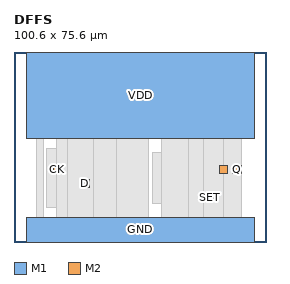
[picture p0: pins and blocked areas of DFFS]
MACRO DFFS
  CLASS CORE ;
  ORIGIN 0 0 ;
  SIZE 100.600 BY 75.600 ;
  SYMMETRY X Y ;
  SITE TR1um_access_site ;
  PIN VDD
    DIRECTION INOUT ;
    USE POWER ;
    PORT
      LAYER M1 ;
        RECT 5.000 41.000 95.600 75.600 ;
    END
  END VDD
  PIN GND
    DIRECTION INOUT ;
    USE GROUND ;
    PORT
      LAYER M1 ;
        RECT 5.000 0.000 95.600 9.800 ;
    END
  END GND
  PIN CK
    DIRECTION INPUT ;
    USE SIGNAL ;
    PORT
      LAYER M2 ;
        RECT 15.600 27.100 19.000 30.500 ;
    END
  END CK
  PIN D
    DIRECTION INPUT ;
    USE SIGNAL ;
    PORT
      LAYER M2 ;
        RECT 26.500 21.600 29.900 25.000 ;
    END
  END D
  PIN Q
    DIRECTION OUTPUT ;
    USE SIGNAL ;
    PORT
      LAYER M2 ;
        RECT 87.100 27.100 90.500 30.500 ;
    END
  END Q
  PIN QB
    DIRECTION OUTPUT ;
    USE SIGNAL ;
    PORT
      LAYER M2 ;
        RECT 81.600 27.100 85.000 30.500 ;
    END
  END QB
  PIN SET
    DIRECTION INPUT ;
    USE SIGNAL ;
    PORT
      LAYER M2 ;
        RECT 76.100 16.100 79.500 19.500 ;
    END
  END SET
  OBS
    LAYER M1 ;
      RECT 76.100 16.100 79.500 22.750 ;
    LAYER M1 ;
      RECT 39.500 15.200 42.100 29.200 ;
    LAYER M1 ;
      RECT 59.900 15.200 62.500 31.600 ;
    LAYER M1 ;
      RECT 26.300 15.200 30.000 35.600 ;
    LAYER M1 ;
      RECT 49.000 17.600 51.600 35.600 ;
    LAYER M1 ;
      RECT 55.100 15.200 64.100 35.600 ;
    LAYER M1 ;
      RECT 13.100 13.600 19.000 37.200 ;
    LAYER M1 ;
      RECT 9.100 6.400 11.700 51.200 ;
    LAYER M1 ;
      RECT 17.100 6.400 24.900 51.200 ;
    LAYER M1 ;
      RECT 21.100 6.400 34.000 51.200 ;
    LAYER M1 ;
      RECT 31.500 6.400 43.200 51.200 ;
    LAYER M1 ;
      RECT 40.700 6.400 53.700 51.200 ;
    LAYER M1 ;
      RECT 58.700 6.400 70.500 51.200 ;
    LAYER M1 ;
      RECT 69.500 6.400 79.300 51.200 ;
    LAYER M1 ;
      RECT 75.500 6.400 85.000 51.200 ;
    LAYER M1 ;
      RECT 83.500 6.400 90.500 51.200 ;
    LAYER V1 ;
      RECT 77.100 17.100 78.500 18.500 ;
    LAYER V1 ;
      RECT 27.500 22.600 28.900 24.000 ;
    LAYER V1 ;
      RECT 16.600 28.100 18.000 29.500 ;
    LAYER V1 ;
      RECT 82.600 28.100 84.000 29.500 ;
    LAYER V1 ;
      RECT 88.100 28.100 89.500 29.500 ;
  END
END DFFS
